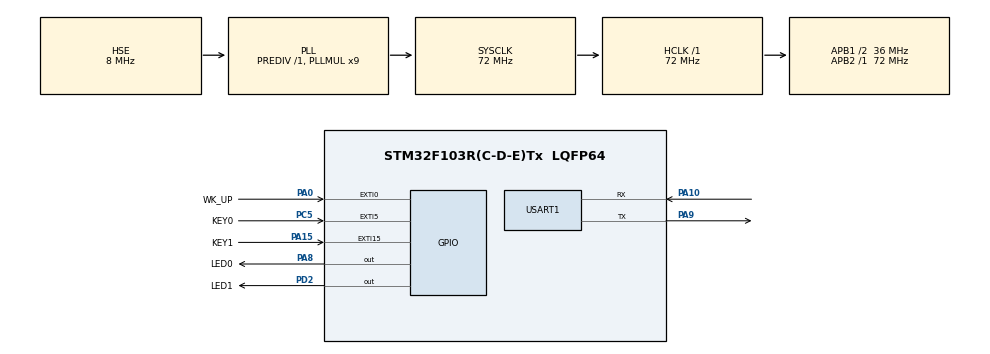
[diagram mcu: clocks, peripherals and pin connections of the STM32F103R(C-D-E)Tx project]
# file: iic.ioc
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Mcu.Family=STM32F1
Mcu.Name=STM32F103R(C-D-E)Tx
Mcu.Package=LQFP64
NVIC.EXTI0_IRQn=true\:1\:0\:true\:false\:true\:true\:true\:true
NVIC.EXTI15_10_IRQn=true\:1\:2\:true\:false\:true\:true\:true\:true
NVIC.EXTI9_5_IRQn=true\:1\:1\:true\:false\:true\:true\:true\:true
NVIC.PriorityGroup=NVIC_PRIORITYGROUP_2
NVIC.USART1_IRQn=true\:1\:3\:true\:false\:true\:true\:true\:true
PA0-WKUP.GPIO_Label=WK_UP
PA0-WKUP.GPIO_PuPd=GPIO_PULLDOWN
PA0-WKUP.Signal=GPXTI0
PA10.Mode=Asynchronous
PA10.Signal=USART1_RX
PA13.Mode=Serial_Wire
PA13.Signal=SYS_JTMS-SWDIO
PA14.Mode=Serial_Wire
PA14.Signal=SYS_JTCK-SWCLK
PA15.GPIO_Label=KEY1
PA15.GPIO_ModeDefaultEXTI=GPIO_MODE_IT_FALLING
PA15.GPIO_PuPd=GPIO_PULLUP
PA15.Signal=GPXTI15
PA8.GPIO_Label=LED0
PA8.PinState=GPIO_PIN_SET
PA8.Signal=GPIO_Output
PA9.Mode=Asynchronous
PA9.Signal=USART1_TX
PC5.GPIO_Label=KEY0
PC5.GPIO_ModeDefaultEXTI=GPIO_MODE_IT_FALLING
PC5.GPIO_PuPd=GPIO_PULLUP
PC5.Signal=GPXTI5
PD0-OSC_IN.Mode=HSE-External-Oscillator
PD0-OSC_IN.Signal=RCC_OSC_IN
PD1-OSC_OUT.Mode=HSE-External-Oscillator
PD1-OSC_OUT.Signal=RCC_OSC_OUT
PD2.GPIO_Label=LED1
PD2.PinState=GPIO_PIN_SET
PD2.Signal=GPIO_Output
ProjectManager.HeapSize=0x200
ProjectManager.StackSize=0x400
ProjectManager.TargetToolchain=STM32CubeIDE
RCC.AHBFreq_Value=72000000
RCC.APB1CLKDivider=RCC_HCLK_DIV2
RCC.APB1Freq_Value=36000000
RCC.APB1TimFreq_Value=72000000
RCC.APB2Freq_Value=72000000
RCC.APB2TimFreq_Value=72000000
RCC.HCLKFreq_Value=72000000
RCC.PLLMUL=RCC_PLL_MUL9
RCC.PLLSourceVirtual=RCC_PLLSOURCE_HSE
RCC.SYSCLKFreq_VALUE=72000000
RCC.SYSCLKSource=RCC_SYSCLKSOURCE_PLLCLK
RCC.USBFreq_Value=72000000
USART1.VirtualMode=VM_ASYNC
board=custom

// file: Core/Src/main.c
/* USER CODE BEGIN Header */
/**
  ******************************************************************************
  * @file           : main.c
  * @brief          : Main program body
  ******************************************************************************
  * @attention
  *
  * <h2><center>&copy; Copyright (c) 2023 STMicroelectronics.
  * All rights reserved.</center></h2>
  *
  * This software component is licensed by ST under BSD 3-Clause license,
  * the "License"; You may not use this file except in compliance with the
  * License. You may obtain a copy of the License at:
  *                        opensource.org/licenses/BSD-3-Clause
  *
  ******************************************************************************
  */
/* USER CODE END Header */
#include "main.h"

/* USER CODE BEGIN Includes */
#include "myiic.h"
#include "usart.h"
#include "24cxx.h"
#include "lcd.h"
/* USER CODE END Includes */

/* USER CODE BEGIN PV */
int uLength;
/* USER CODE END PV */

void SystemClock_Config(void);
static void MX_GPIO_Init(void);

/* USER CODE BEGIN 0 */
//要写入到24c02的字符串数组
// const uint8_t TEXT_Buffer[]={"CS301 IIC TEST DEMO"};
// #define SIZE sizeof(TEXT_Buffer)
/* USER CODE END 0 */

int main(void)
{

  /* MCU Configuration--------------------------------------------------------*/

  /* Reset of all peripherals, Initializes the Flash interface and the Systick. */
  HAL_Init();

  /* Configure the system clock */
  SystemClock_Config();

  /* Initialize all configured peripherals */
  MX_GPIO_Init();
  MX_USART1_UART_Init();
  /* USER CODE BEGIN 2 */

  uint16_t i=0;
    uint8_t datatemp[1024];
    lcd_init();

    lcd_show_string(40,50,200,16,16,"CS301", RED);
    lcd_show_string(40,70,200,16,16,"IIC TEST", RED);
    lcd_show_string(40,90,200,16,16,"KEY1:Write  KEY0:Read", RED);	//显示提示信息

    AT24CXX_Init();
    HAL_UART_Receive_IT(&huart1, (uint8_t *) rxBuffer, 1);
  /* USER CODE END 2 */

  /* Infinite loop */
  /* USER CODE BEGIN WHILE */
    	while(AT24CXX_Check())
    	{
    		lcd_show_string(40,120,200,16,16,"24C02 Check Failed!", RED);
    		HAL_Delay(500);
    		lcd_show_string(40,120,200,16,16,"Please Check!      ", RED);
    		HAL_Delay(500);
    		HAL_GPIO_TogglePin(LED0_GPIO_Port, LED0_Pin);//LED0闪烁
    	}

    	lcd_show_string(40,120,200,16,16,"24C02 Ready!", RED);

    while (1)
    {
    /* USER CODE END WHILE */

    /* USER CODE BEGIN 3 */
  	  		if(HAL_GPIO_ReadPin(KEY0_GPIO_Port, KEY0_Pin) == GPIO_PIN_RESET)//KEY0按下,读取字符串并显示
  	  		{
  	  			lcd_fill(0,170,239,319,WHITE);
  	  			lcd_show_string(40,170,200,16,16,"Start Reading 24C02.... ", BLUE);
  	  			AT24CXX_Read(0,datatemp,1024);
  	  			lcd_fill(0,170,239,319,WHITE);
  	  			lcd_show_string(40,170,200,16,16,"The Data Read Is:  ", BLUE);//提示传�?�完�???
  	  			lcd_show_string(40,190,200,16,16,datatemp,BLUE);//显示读到的字符串
  	  			// HAL_UART_Transmit(&huart1, (uint8_t *)&datatemp, SIZE, 0xffff);
  	  		}
  	  		i++;
  	  		HAL_Delay(50);
  	  		if(i==20)
  	  		{
  	  			HAL_GPIO_TogglePin(LED0_GPIO_Port, LED0_Pin);//提示系统正在运行
  	  			i=0;
  	  		}
    }
  /* USER CODE END 3 */
}

void SystemClock_Config(void)
{
  RCC_OscInitTypeDef RCC_OscInitStruct = {0};
  RCC_ClkInitTypeDef RCC_ClkInitStruct = {0};

  /** Initializes the RCC Oscillators according to the specified parameters
  * in the RCC_OscInitTypeDef structure.
  */
  RCC_OscInitStruct.OscillatorType = RCC_OSCILLATORTYPE_HSE;
  RCC_OscInitStruct.HSEState = RCC_HSE_ON;
  RCC_OscInitStruct.HSEPredivValue = RCC_HSE_PREDIV_DIV1;
  RCC_OscInitStruct.HSIState = RCC_HSI_ON;
  RCC_OscInitStruct.PLL.PLLState = RCC_PLL_ON;
  RCC_OscInitStruct.PLL.PLLSource = RCC_PLLSOURCE_HSE;
  RCC_OscInitStruct.PLL.PLLMUL = RCC_PLL_MUL9;
  if (HAL_RCC_OscConfig(&RCC_OscInitStruct) != HAL_OK)
  {
    Error_Handler();
  }
  /** Initializes the CPU, AHB and APB buses clocks
  */
  RCC_ClkInitStruct.ClockType = RCC_CLOCKTYPE_HCLK|RCC_CLOCKTYPE_SYSCLK
                              |RCC_CLOCKTYPE_PCLK1|RCC_CLOCKTYPE_PCLK2;
  RCC_ClkInitStruct.SYSCLKSource = RCC_SYSCLKSOURCE_PLLCLK;
  RCC_ClkInitStruct.AHBCLKDivider = RCC_SYSCLK_DIV1;
  RCC_ClkInitStruct.APB1CLKDivider = RCC_HCLK_DIV2;
  RCC_ClkInitStruct.APB2CLKDivider = RCC_HCLK_DIV1;

  if (HAL_RCC_ClockConfig(&RCC_ClkInitStruct, FLASH_LATENCY_2) != HAL_OK)
  {
    Error_Handler();
  }
}

static void MX_GPIO_Init(void)
{
  GPIO_InitTypeDef GPIO_InitStruct = {0};

  /* GPIO Ports Clock Enable */
  __HAL_RCC_GPIOD_CLK_ENABLE();
  __HAL_RCC_GPIOC_CLK_ENABLE();
  __HAL_RCC_GPIOA_CLK_ENABLE();

  /*Configure GPIO pin Output Level */
  HAL_GPIO_WritePin(LED0_GPIO_Port, LED0_Pin, GPIO_PIN_RESET);

  /*Configure GPIO pin Output Level */
  HAL_GPIO_WritePin(GPIOC, IIC_SDA_Pin|IIC_SCL_Pin, GPIO_PIN_RESET);

  /*Configure GPIO pin Output Level */
  HAL_GPIO_WritePin(LED1_GPIO_Port, LED1_Pin, GPIO_PIN_RESET);

  /*Configure GPIO pin : KEY0_Pin */
  GPIO_InitStruct.Pin = KEY0_Pin;
  GPIO_InitStruct.Mode = GPIO_MODE_INPUT;
  GPIO_InitStruct.Pull = GPIO_PULLUP;
  HAL_GPIO_Init(KEY0_GPIO_Port, &GPIO_InitStruct);

  /*Configure GPIO pin : LED0_Pin */
  GPIO_InitStruct.Pin = LED0_Pin;
  GPIO_InitStruct.Mode = GPIO_MODE_OUTPUT_PP;
  GPIO_InitStruct.Pull = GPIO_NOPULL;
  GPIO_InitStruct.Speed = GPIO_SPEED_FREQ_LOW;
  HAL_GPIO_Init(LED0_GPIO_Port, &GPIO_InitStruct);

  /*Configure GPIO pin : KEY1_Pin */
  GPIO_InitStruct.Pin = KEY1_Pin;
  GPIO_InitStruct.Mode = GPIO_MODE_INPUT;
  GPIO_InitStruct.Pull = GPIO_PULLUP;
  HAL_GPIO_Init(KEY1_GPIO_Port, &GPIO_InitStruct);

  /*Configure GPIO pin : IIC_SDA_Pin */
  GPIO_InitStruct.Pin = IIC_SDA_Pin;
  GPIO_InitStruct.Mode = GPIO_MODE_OUTPUT_OD;
  GPIO_InitStruct.Pull = GPIO_NOPULL;
  GPIO_InitStruct.Speed = GPIO_SPEED_FREQ_LOW;
  HAL_GPIO_Init(IIC_SDA_GPIO_Port, &GPIO_InitStruct);

  /*Configure GPIO pin : IIC_SCL_Pin */
  GPIO_InitStruct.Pin = IIC_SCL_Pin;
  GPIO_InitStruct.Mode = GPIO_MODE_OUTPUT_PP;
  GPIO_InitStruct.Pull = GPIO_NOPULL;
  GPIO_InitStruct.Speed = GPIO_SPEED_FREQ_LOW;
  HAL_GPIO_Init(IIC_SCL_GPIO_Port, &GPIO_InitStruct);

  /*Configure GPIO pin : LED1_Pin */
  GPIO_InitStruct.Pin = LED1_Pin;
  GPIO_InitStruct.Mode = GPIO_MODE_OUTPUT_PP;
  GPIO_InitStruct.Pull = GPIO_NOPULL;
  GPIO_InitStruct.Speed = GPIO_SPEED_FREQ_LOW;
  HAL_GPIO_Init(LED1_GPIO_Port, &GPIO_InitStruct);

}

void Error_Handler(void)
{
  __disable_irq();
  while (1)
  {
  }
}

/************************ (C) COPYRIGHT STMicroelectronics *****END OF FILE****/
